One B-rep face of a CAD part: STEP entity #1489.
In plain terms, the planar face has unit normal (1, 0, 0).
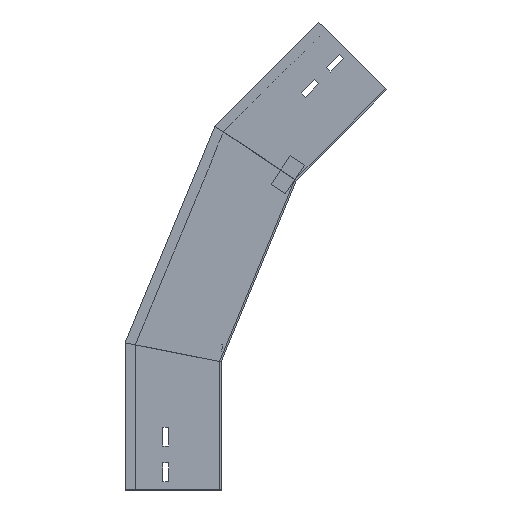
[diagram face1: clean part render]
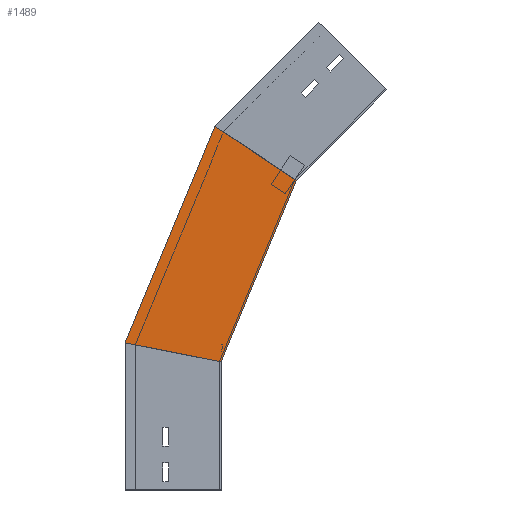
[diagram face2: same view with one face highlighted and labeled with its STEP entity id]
Its self-contained STEP definition (entity closure, numbers rounded to 3 decimals):
#42 = DIRECTION ( 'NONE',  ( 0., 0., -1. ) ) ;
#107 = EDGE_CURVE ( 'NONE', #265, #1053, #1114, .T. ) ;
#132 = ORIENTED_EDGE ( 'NONE', *, *, #252, .F. ) ;
#252 = EDGE_CURVE ( 'NONE', #265, #1007, #584, .T. ) ;
#265 = VERTEX_POINT ( 'NONE', #1171 ) ;
#269 = DIRECTION ( 'NONE',  ( 1., 0., 0. ) ) ;
#283 = EDGE_CURVE ( 'NONE', #1053, #1098, #631, .T. ) ;
#289 = DIRECTION ( 'NONE',  ( 0., -0.831, -0.556 ) ) ;
#303 = CARTESIAN_POINT ( 'NONE',  ( 0., 7.356, 426.218 ) ) ;
#386 = VECTOR ( 'NONE', #1085, 1000. ) ;
#436 = DIRECTION ( 'NONE',  ( 0., -0.383, 0.924 ) ) ;
#501 = AXIS2_PLACEMENT_3D ( 'NONE', #504, #269, #42 ) ;
#504 = CARTESIAN_POINT ( 'NONE',  ( 0., 9.458, 127.166 ) ) ;
#526 = PLANE ( 'NONE',  #501 ) ;
#584 = LINE ( 'NONE', #1036, #1049 ) ;
#608 = EDGE_LOOP ( 'NONE', ( #818, #1150, #1249, #132 ) ) ;
#627 = LINE ( 'NONE', #1328, #386 ) ;
#631 = LINE ( 'NONE', #749, #1151 ) ;
#674 = VECTOR ( 'NONE', #436, 1000. ) ;
#749 = CARTESIAN_POINT ( 'NONE',  ( 0., -129.335, 334.885 ) ) ;
#818 = ORIENTED_EDGE ( 'NONE', *, *, #107, .T. ) ;
#998 = CARTESIAN_POINT ( 'NONE',  ( 0., 113.395, 170.218 ) ) ;
#1007 = VERTEX_POINT ( 'NONE', #1456 ) ;
#1036 = CARTESIAN_POINT ( 'NONE',  ( 0., -28.701, 144.291 ) ) ;
#1049 = VECTOR ( 'NONE', #1282, 1000. ) ;
#1053 = VERTEX_POINT ( 'NONE', #303 ) ;
#1085 = DIRECTION ( 'NONE',  ( 0., -0.383, 0.924 ) ) ;
#1098 = VERTEX_POINT ( 'NONE', #1386 ) ;
#1114 = LINE ( 'NONE', #998, #674 ) ;
#1150 = ORIENTED_EDGE ( 'NONE', *, *, #283, .T. ) ;
#1151 = VECTOR ( 'NONE', #289, 1000. ) ;
#1171 = CARTESIAN_POINT ( 'NONE',  ( 0., 112.5, 172.378 ) ) ;
#1249 = ORIENTED_EDGE ( 'NONE', *, *, #1430, .F. ) ;
#1282 = DIRECTION ( 'NONE',  ( 0., -0.981, -0.195 ) ) ;
#1317 = FACE_OUTER_BOUND ( 'NONE', #608, .T. ) ;
#1328 = CARTESIAN_POINT ( 'NONE',  ( 0., 9.458, 127.166 ) ) ;
#1386 = CARTESIAN_POINT ( 'NONE',  ( 0., -88.017, 362.492 ) ) ;
#1430 = EDGE_CURVE ( 'NONE', #1007, #1098, #627, .T. ) ;
#1456 = CARTESIAN_POINT ( 'NONE',  ( 0., 0., 150. ) ) ;
#1489 = ADVANCED_FACE ( 'NONE', ( #1317 ), #526, .T. ) ;
